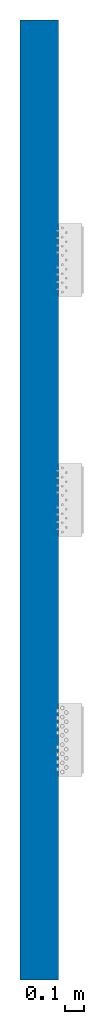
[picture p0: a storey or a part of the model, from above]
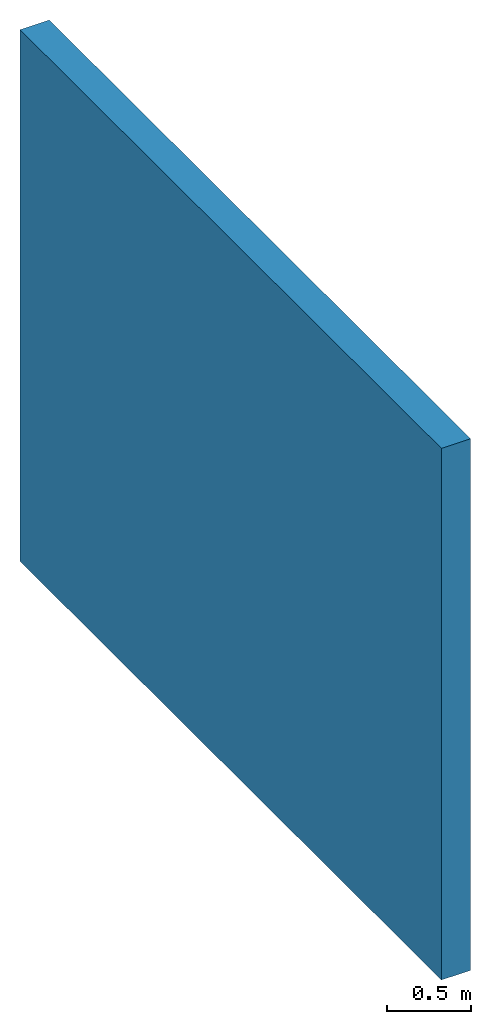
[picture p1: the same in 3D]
Properties of the parts of a building model (IFC2X3)

# File
Description: ViewDefinition [CoordinationView_V2.0]
File name: Número de proyecto
Time: 2016-11-14T12:49:44
Written by: The EXPRESS Data Manager Version 5.02.0100.07 : 28 Aug 2013
Made in: 20160225_1515(x64) - Exporter 17.0.416.0 - Alternate UI 17.12.14.0
Comment: STEP Physical File produced by: The EXPRESS Data Manager Version 5.02.0100.07 : 28 Aug 2013 * Module: EDMstepFileFactory/EDMstandAlone * Creation date: Mon Nov 14 12:49:44 2016 * Host: Andromeda * Database: C:\Users\MODELI~1\AppData\Local\Temp\{659E1384-E6DE-44E8-AB32-4E3F050A8568}\ifc * Database version: 5507 * Database creation date: Mon Nov 14 12:49:41 2016 * Schema: IFC2X3 * Model: DataRepository.ifc * Model creation date: Mon Nov 14 12:49:42 2016 * Header model: DataRepository.ifc_HeaderModel * Header model creation date: Mon Nov 14 12:49:42 2016 * EDMuser: sdai-user * EDMgroup: sdai-group * License ID and type: 5605 : Permanent license. Expiry date: * EDMstepFileFactory options: 020000

# IfcProject, Número de proyecto
LongName: REFORMA DE LA SEDE DE MODELICAL; Phase: PROYECTO BÁSICO

# IfcSite, Default
RefLatitude: 40, 25, 0, 86975; RefLongitude: -3, -42, -1, -243858; RefElevation: 0 m

# IfcBuilding
Pset_BuildingCommon - NumberOfStoreys: 1

# IfcBuildingStorey, Level 0
LongName: Level 0; Elevation: 37.55 m

# IfcBuildingElementProxy: ESS-RP1r-Supra, HoneyWell-RP1r-Supra-VSN-RP1r-ESS-RP1r-Supra:ESS-RP1r-Supra:828526
In: Level 0
Type - Classification: D5030700 (Uniformat); Material: Steel,Black
Pset_BuildingElementProxyCommon - Reference: ESS-RP1r-Supra
Pset_ManufacturerTypeInformation - Manufacturer: Honeywell

# IfcBuildingElementProxy: RP1r-Supra, HoneyWell-RP1r-Supra-VSN-RP1r-ESS-RP1r-Supra:RP1r-Supra:830595
In: Level 0
Type - Classification: D5030700 (Uniformat); Material: Steel,Black
Pset_BuildingElementProxyCommon - Reference: RP1r-Supra
Pset_ManufacturerTypeInformation - Manufacturer: Honeywell

# IfcBuildingElementProxy: VSN-RP1r+, HoneyWell-RP1r-Supra-VSN-RP1r-ESS-RP1r-Supra:VSN-RP1r+:834774
In: Level 0
Type - Classification: D5030700 (Uniformat)
Pset_BuildingElementProxyCommon - Reference: VSN-RP1r+
Pset_ManufacturerTypeInformation - Manufacturer: Honeywell

# IfcWallStandardCase: Basic Wall:200mm, Basic Wall:200mm:826588
In: Level 0
Type - PredefinedType: STANDARD; Material: Default 0.2 m
Pset_WallCommon - Reference: 200mm; LoadBearing: no; ExtendToStructure: no; IsExternal: yes
